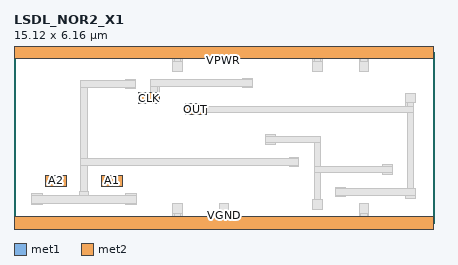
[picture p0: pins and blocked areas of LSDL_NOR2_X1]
MACRO LSDL_NOR2_X1
 CLASS CORE ;
 FOREIGN LSDL_NOR2_X1 0 0 ;
 SIZE 15.120000000000001 BY 6.16 ;
 ORIGIN 0 0 ;
 SYMMETRY X Y R90 ;
 SITE unit ;
  PIN VPWR
   DIRECTION INOUT ;
   USE POWER ;
   SHAPE ABUTMENT ;
    PORT
     CLASS CORE ;
       LAYER met1 ;
        RECT 0.00000000 5.92000000 15.12000000 6.40000000 ;
       LAYER met2 ;
        RECT 0.00000000 5.92000000 15.12000000 6.40000000 ;
    END
  END VPWR

  PIN VGND
   DIRECTION INOUT ;
   USE GROUND ;
   SHAPE ABUTMENT ;
    PORT
     CLASS CORE ;
       LAYER met1 ;
        RECT 0.00000000 -0.24000000 15.12000000 0.24000000 ;
       LAYER met2 ;
        RECT 0.00000000 -0.24000000 15.12000000 0.24000000 ;
    END
  END VGND

  PIN OUT
   DIRECTION OUTPUT ;
   USE SIGNAL ;
   SHAPE ABUTMENT ;
    PORT
     CLASS CORE ;
       LAYER met2 ;
        RECT 6.16000000 3.89200000 6.92000000 4.29200000 ;
    END
  END OUT

  PIN A1
   DIRECTION INPUT ;
   USE SIGNAL ;
   SHAPE ABUTMENT ;
    PORT
     CLASS CORE ;
       LAYER met2 ;
        RECT 3.16000000 1.32700000 3.92000000 1.72700000 ;
    END
  END A1

  PIN CLK
   DIRECTION INPUT ;
   USE SIGNAL ;
   SHAPE ABUTMENT ;
    PORT
     CLASS CORE ;
       LAYER met2 ;
        RECT 4.48000000 4.30000000 5.24000000 4.70000000 ;
    END
  END CLK

  PIN A2
   DIRECTION INPUT ;
   USE SIGNAL ;
   SHAPE ABUTMENT ;
    PORT
     CLASS CORE ;
       LAYER met2 ;
        RECT 1.12000000 1.32700000 1.88000000 1.72700000 ;
    END
  END A2

 OBS
    LAYER polycont ;
     RECT 4.93000000 4.39000000 5.15000000 4.61000000 ;
     RECT 8.29000000 4.92700000 8.51000000 5.14700000 ;
     RECT 1.57000000 1.41700000 1.79000000 1.63700000 ;
     RECT 11.65000000 1.01200000 11.87000000 1.23200000 ;
     RECT 6.61000000 3.98200000 6.83000000 4.20200000 ;
     RECT 9.97000000 2.09200000 10.19000000 2.31200000 ;
     RECT 3.25000000 1.41700000 3.47000000 1.63700000 ;
     RECT 13.33000000 1.82200000 13.55000000 2.04200000 ;

    LAYER pdiffc ;
     RECT 14.17000000 4.39000000 14.39000000 4.61000000 ;
     RECT 5.77000000 5.53000000 5.99000000 5.75000000 ;
     RECT 10.81000000 5.53000000 11.03000000 5.75000000 ;
     RECT 12.49000000 5.53000000 12.71000000 5.75000000 ;
     RECT 4.09000000 4.89000000 4.31000000 5.11000000 ;
     RECT 9.13000000 2.89000000 9.35000000 3.11000000 ;

    LAYER ndiffc ;
     RECT 14.17000000 0.95000000 14.39000000 1.17000000 ;
     RECT 2.41000000 0.85000000 2.63000000 1.07000000 ;
     RECT 0.73000000 0.74200000 0.95000000 0.96200000 ;
     RECT 4.09000000 0.74200000 4.31000000 0.96200000 ;
     RECT 5.77000000 0.41000000 5.99000000 0.63000000 ;
     RECT 7.45000000 0.41000000 7.67000000 0.63000000 ;
     RECT 12.49000000 0.41000000 12.71000000 0.63000000 ;
     RECT 10.81000000 0.55000000 11.03000000 0.77000000 ;

    LAYER met1 ;
     RECT 5.71000000 0.24000000 5.76500000 0.35000000 ;
     RECT 5.99500000 0.24000000 6.05000000 0.35000000 ;
     RECT 7.39000000 0.24000000 7.44500000 0.35000000 ;
     RECT 7.67500000 0.24000000 7.73000000 0.35000000 ;
     RECT 12.43000000 0.24000000 12.48500000 0.35000000 ;
     RECT 12.71500000 0.24000000 12.77000000 0.35000000 ;
     RECT 14.11000000 4.20700000 14.16500000 4.33000000 ;
     RECT 5.15500000 4.70000000 5.24000000 4.92200000 ;
     RECT 5.71000000 5.81000000 5.76500000 5.92000000 ;
     RECT 5.99500000 5.81000000 6.05000000 5.92000000 ;
     RECT 10.75000000 5.81000000 10.80500000 5.92000000 ;
     RECT 11.03500000 5.81000000 11.09000000 5.92000000 ;
     RECT 12.43000000 5.81000000 12.48500000 5.92000000 ;
     RECT 12.71500000 5.81000000 12.77000000 5.92000000 ;
     RECT 4.84000000 4.30000000 5.24000000 4.70000000 ;
     RECT 4.92500000 4.70000000 5.15500000 4.92200000 ;
     RECT 8.23000000 4.86700000 8.57000000 4.92200000 ;
     RECT 4.92500000 4.92200000 8.57000000 5.15200000 ;
     RECT 8.23000000 5.15200000 8.57000000 5.20700000 ;
     RECT 1.48000000 1.32700000 1.88000000 1.72700000 ;
     RECT 11.59000000 0.95200000 11.93000000 1.00700000 ;
     RECT 14.11000000 0.89000000 14.45000000 1.00700000 ;
     RECT 11.59000000 1.00700000 14.45000000 1.23000000 ;
     RECT 11.59000000 1.23000000 14.39500000 1.23700000 ;
     RECT 11.59000000 1.23700000 11.93000000 1.29200000 ;
     RECT 6.52000000 3.89200000 6.92000000 3.97700000 ;
     RECT 14.16500000 1.23700000 14.39500000 3.97700000 ;
     RECT 6.52000000 3.97700000 14.39500000 4.20700000 ;
     RECT 6.52000000 4.20700000 6.92000000 4.29200000 ;
     RECT 14.16500000 4.20700000 14.39500000 4.33000000 ;
     RECT 14.11000000 4.33000000 14.45000000 4.67000000 ;
     RECT 5.71000000 5.47000000 6.05000000 5.81000000 ;
     RECT 10.75000000 5.47000000 11.09000000 5.81000000 ;
     RECT 12.43000000 5.47000000 12.77000000 5.81000000 ;
     RECT 5.76500000 5.81000000 5.99500000 5.92000000 ;
     RECT 10.80500000 5.81000000 11.03500000 5.92000000 ;
     RECT 12.48500000 5.81000000 12.71500000 5.92000000 ;
     RECT 0.00000000 5.92000000 15.12000000 6.40000000 ;
     RECT 2.35000000 0.79000000 2.69000000 1.13000000 ;
     RECT 2.40500000 1.13000000 2.63500000 2.08700000 ;
     RECT 9.91000000 2.03200000 10.25000000 2.08700000 ;
     RECT 2.40500000 2.08700000 10.25000000 2.31700000 ;
     RECT 9.91000000 2.31700000 10.25000000 2.37200000 ;
     RECT 2.40500000 2.31700000 2.63500000 4.88500000 ;
     RECT 4.03000000 4.83000000 4.37000000 4.88500000 ;
     RECT 2.40500000 4.88500000 4.37000000 5.11500000 ;
     RECT 4.03000000 5.11500000 4.37000000 5.17000000 ;
     RECT 3.16000000 1.32700000 3.56000000 1.72700000 ;
     RECT 0.64000000 0.65200000 1.04000000 1.05200000 ;
     RECT 4.00000000 0.65200000 4.40000000 1.05200000 ;
     RECT 0.00000000 -0.24000000 15.12000000 0.24000000 ;
     RECT 5.76500000 0.24000000 5.99500000 0.35000000 ;
     RECT 7.44500000 0.24000000 7.67500000 0.35000000 ;
     RECT 12.48500000 0.24000000 12.71500000 0.35000000 ;
     RECT 5.71000000 0.35000000 6.05000000 0.69000000 ;
     RECT 7.39000000 0.35000000 7.73000000 0.69000000 ;
     RECT 12.43000000 0.35000000 12.77000000 0.69000000 ;
     RECT 10.75000000 0.49000000 11.09000000 0.83000000 ;
     RECT 10.80500000 0.83000000 11.03500000 1.81700000 ;
     RECT 13.27000000 1.76200000 13.61000000 1.81700000 ;
     RECT 10.80500000 1.81700000 13.61000000 2.04700000 ;
     RECT 13.27000000 2.04700000 13.61000000 2.10200000 ;
     RECT 9.07000000 2.83000000 9.41000000 2.88500000 ;
     RECT 10.80500000 2.04700000 11.03500000 2.88500000 ;
     RECT 9.07000000 2.88500000 11.03500000 3.11500000 ;
     RECT 9.07000000 3.11500000 9.41000000 3.17000000 ;

    LAYER via1 ;
     RECT 4.91000000 4.37000000 5.17000000 4.63000000 ;
     RECT 1.55000000 1.39700000 1.81000000 1.65700000 ;
     RECT 6.59000000 3.96200000 6.85000000 4.22200000 ;
     RECT 0.71000000 6.03000000 0.97000000 6.29000000 ;
     RECT 2.39000000 6.03000000 2.65000000 6.29000000 ;
     RECT 4.07000000 6.03000000 4.33000000 6.29000000 ;
     RECT 5.75000000 6.03000000 6.01000000 6.29000000 ;
     RECT 7.43000000 6.03000000 7.69000000 6.29000000 ;
     RECT 9.11000000 6.03000000 9.37000000 6.29000000 ;
     RECT 10.79000000 6.03000000 11.05000000 6.29000000 ;
     RECT 12.47000000 6.03000000 12.73000000 6.29000000 ;
     RECT 14.15000000 6.03000000 14.41000000 6.29000000 ;
     RECT 3.23000000 1.39700000 3.49000000 1.65700000 ;
     RECT 0.71000000 0.72200000 0.97000000 0.98200000 ;
     RECT 4.07000000 0.72200000 4.33000000 0.98200000 ;
     RECT 0.71000000 -0.13000000 0.97000000 0.13000000 ;
     RECT 2.39000000 -0.13000000 2.65000000 0.13000000 ;
     RECT 4.07000000 -0.13000000 4.33000000 0.13000000 ;
     RECT 5.75000000 -0.13000000 6.01000000 0.13000000 ;
     RECT 7.43000000 -0.13000000 7.69000000 0.13000000 ;
     RECT 9.11000000 -0.13000000 9.37000000 0.13000000 ;
     RECT 10.79000000 -0.13000000 11.05000000 0.13000000 ;
     RECT 12.47000000 -0.13000000 12.73000000 0.13000000 ;
     RECT 14.15000000 -0.13000000 14.41000000 0.13000000 ;

    LAYER met2 ;
     RECT 4.84000000 4.30000000 5.24000000 4.70000000 ;
     RECT 1.48000000 1.32700000 1.88000000 1.72700000 ;
     RECT 6.52000000 3.89200000 6.92000000 4.29200000 ;
     RECT 0.00000000 5.92000000 15.12000000 6.40000000 ;
     RECT 3.16000000 1.32700000 3.56000000 1.72700000 ;
     RECT 0.64000000 0.65200000 1.04000000 0.71200000 ;
     RECT 4.00000000 0.65200000 4.40000000 0.71200000 ;
     RECT 0.64000000 0.71200000 4.40000000 0.99200000 ;
     RECT 0.64000000 0.99200000 1.04000000 1.05200000 ;
     RECT 4.00000000 0.99200000 4.40000000 1.05200000 ;
     RECT 0.00000000 -0.24000000 15.12000000 0.24000000 ;

 END
END LSDL_NOR2_X1
